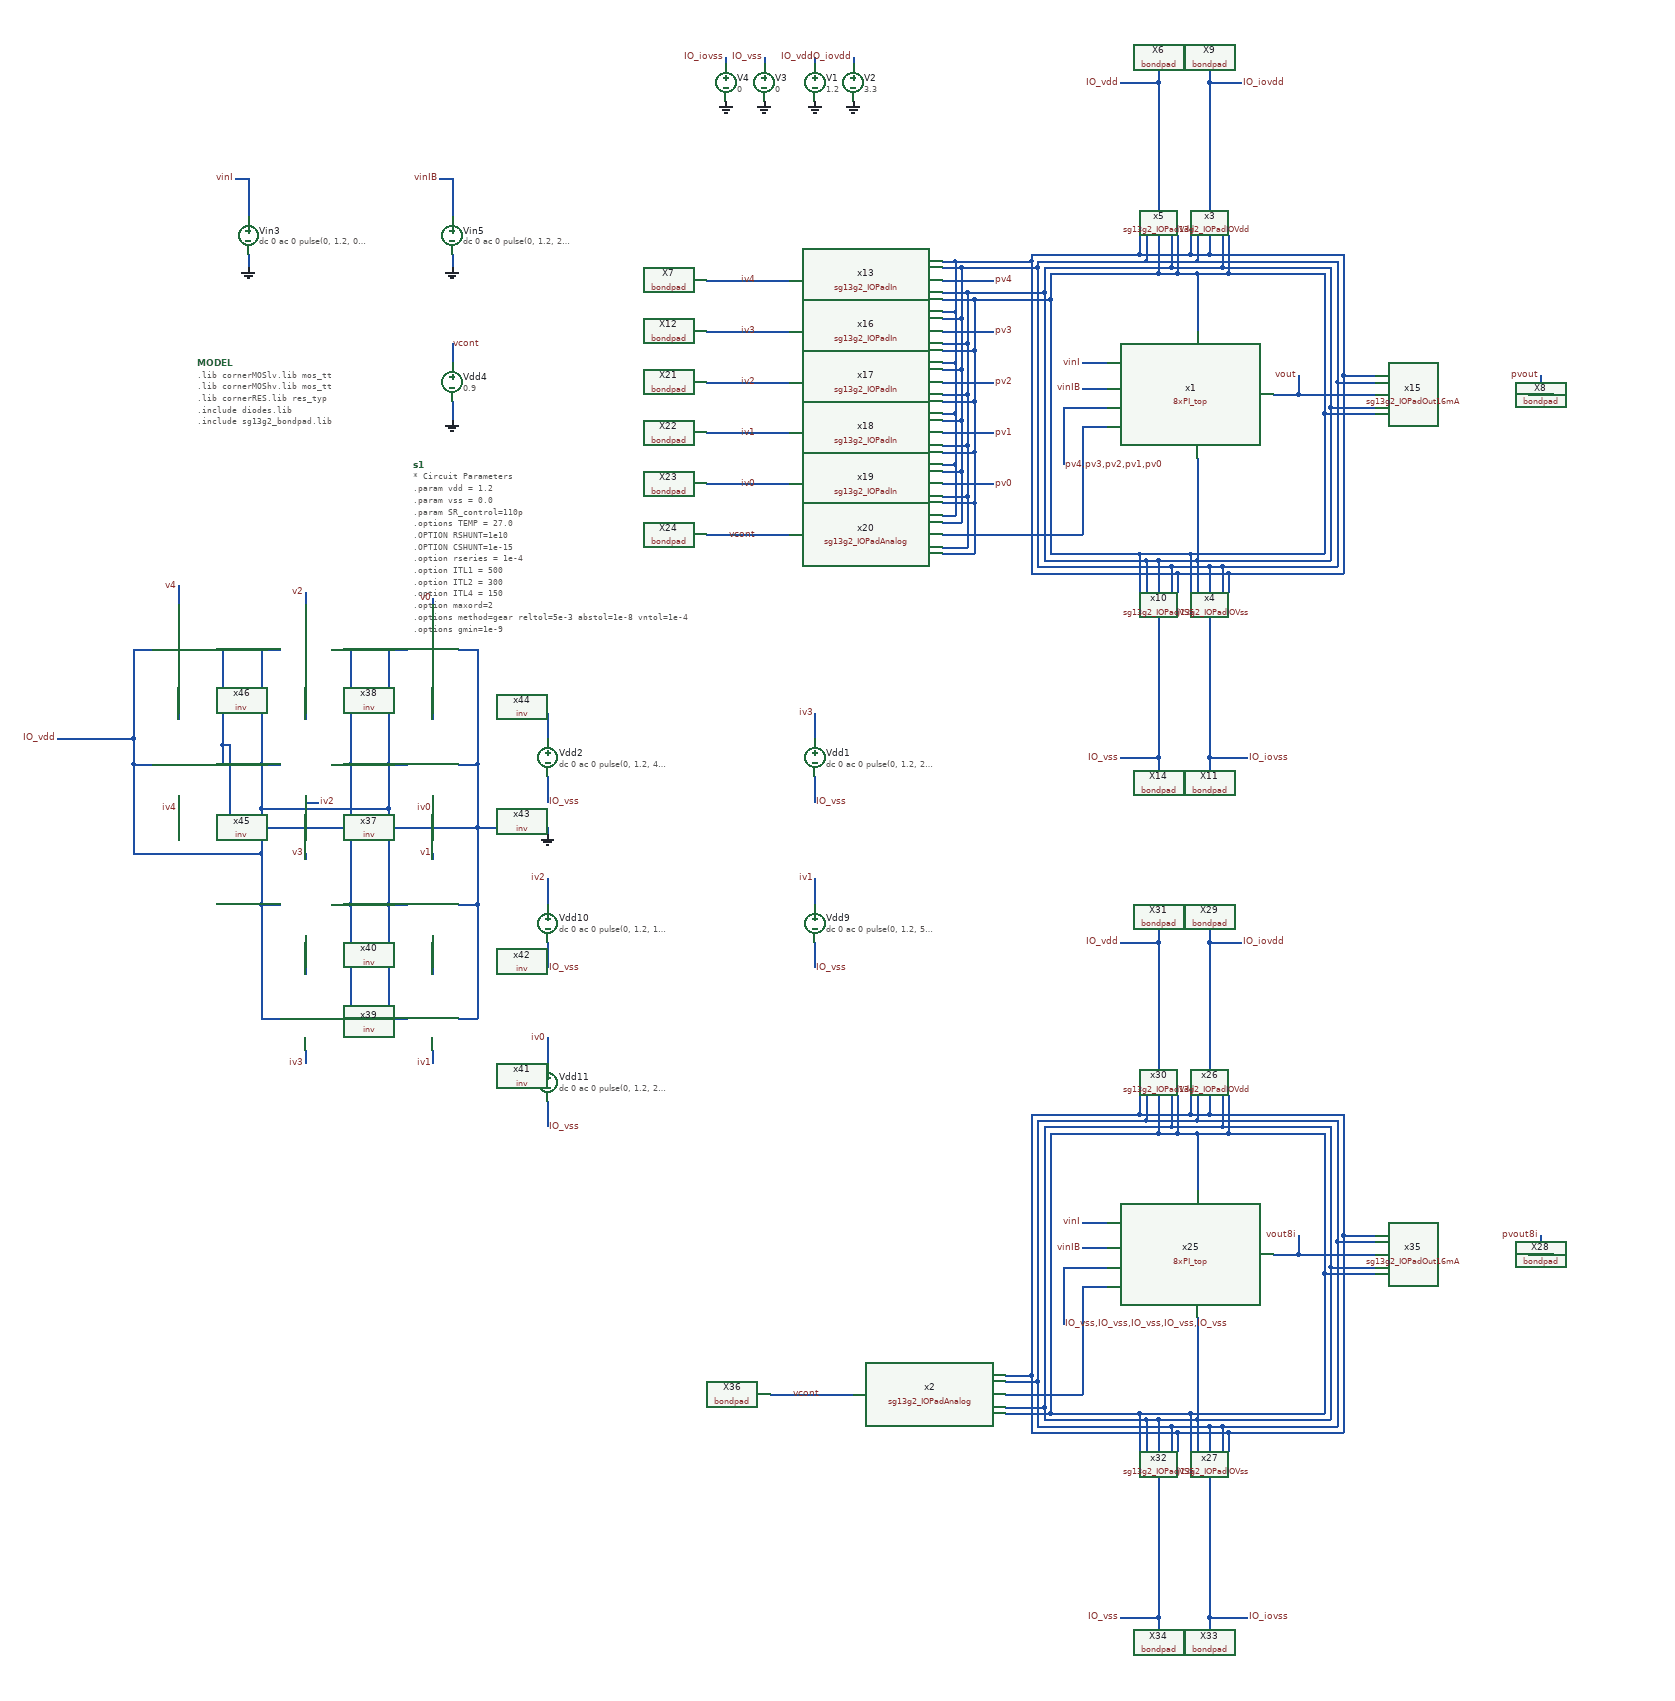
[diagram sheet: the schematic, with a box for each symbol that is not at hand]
v {xschem version=3.4.8RC file_version=1.3}
G {}
K {}
V {}
S {}
F {}
E {}
N -1470 -690 -1470 -670 {
lab=GND}
N -1470 -810 -1470 -750 {
lab=vinI}
N -1490 -810 -1470 -810 {
lab=vinI}
N -1150 -690 -1150 -670 {
lab=GND}
N -1150 -810 -1150 -750 {
lab=vinIB}
N -1170 -810 -1150 -810 {
lab=vinIB}
N -1000 290 -1000 330 {lab=iv2}
N -580 290 -580 330 {lab=iv1}
N -1000 390 -1000 430 {lab=IO_vss}
N -580 390 -580 430 {lab=IO_vss}
N -1000 540 -1000 580 {lab=iv0}
N -1000 640 -1000 680 {lab=IO_vss}
N -1000 30 -1000 70 {lab=iv4}
N -580 30 -580 70 {lab=iv3}
N -580 130 -580 170 {lab=IO_vss}
N -1150 -550 -1150 -520 {lab=vcont}
N -1150 -460 -1150 -430 {lab=GND}
N -160 -520 -120 -520 {lab=vinI}
N -160 -480 -120 -480 {lab=vinIB}
N -160 -420 -120 -420 {lab=#net1}
N 180 -470 300 -470 {lab=vout}
N 70 -660 220 -660 {lab=IO_vdd}
N 20 -680 240 -680 {lab=IO_iovss}
N 60 -200 240 -200 {lab=IO_iovss}
N 70 -190 250 -190 {lab=IO_iovdd}
N -220 -630 -220 -210 {lab=IO_vss}
N -230 -670 -230 -200 {lab=IO_iovss}
N -240 -680 -240 -190 {lab=IO_iovdd}
N 60 -670 230 -670 {lab=IO_vss}
N -210 -620 -210 -220 {lab=IO_vdd}
N -220 -210 -60 -210 {lab=IO_vss}
N 230 -450 230 -210 {lab=IO_vss}
N 240 -490 240 -200 {lab=IO_iovss}
N 220 -440 220 -220 {lab=IO_vdd}
N -520 -1000 -520 -990 {
lab=IO_iovdd}
N -720 -1000 -720 -990 {
lab=IO_iovss}
N 10 -720 10 -690 {lab=IO_iovdd}
N -70 -690 10 -690 {lab=IO_iovdd}
N 20 -720 20 -680 {lab=IO_iovss}
N -60 -680 20 -680 {lab=IO_iovss}
N 60 -720 60 -670 {lab=IO_vss}
N -20 -670 60 -670 {lab=IO_vss}
N 70 -720 70 -660 {lab=IO_vdd}
N 20 -660 20 -570 {lab=IO_vdd}
N -10 -660 20 -660 {lab=IO_vdd}
N 40 -690 250 -690 {lab=IO_iovdd}
N 70 -190 70 -160 {lab=IO_iovdd}
N -10 -190 70 -190 {lab=IO_iovdd}
N 60 -200 60 -160 {lab=IO_iovss}
N 40 -200 60 -200 {lab=IO_iovss}
N 20 -210 230 -210 {lab=IO_vss}
N 10 -220 10 -160 {lab=IO_vdd}
N -70 -220 10 -220 {lab=IO_vdd}
N 40 -960 90 -960 {lab=IO_iovdd}
N 40 -980 40 -960 {lab=IO_iovdd}
N 20 -660 70 -660 {lab=IO_vdd}
N 40 -960 40 -690 {lab=IO_iovdd}
N 10 -690 40 -690 {lab=IO_iovdd}
N -70 -720 -70 -690 {lab=IO_iovdd}
N -240 -690 -70 -690 {lab=IO_iovdd}
N -60 -720 -60 -680 {lab=IO_iovss}
N -230 -680 -60 -680 {lab=IO_iovss}
N -20 -720 -20 -670 {lab=IO_vss}
N -220 -670 -20 -670 {lab=IO_vss}
N -10 -720 -10 -660 {lab=IO_vdd}
N -40 -660 -10 -660 {lab=IO_vdd}
N -40 -960 -40 -660 {lab=IO_vdd}
N -210 -660 -40 -660 {lab=IO_vdd}
N -580 -1000 -580 -990 {
lab=IO_vdd}
N -660 -1000 -660 -990 {
lab=IO_vss}
N -10 -190 -10 -160 {lab=IO_iovdd}
N -240 -190 -10 -190 {lab=IO_iovdd}
N -20 -200 -20 -160 {lab=IO_iovss}
N -60 -210 -60 -160 {lab=IO_vss}
N -70 -220 -70 -160 {lab=IO_vdd}
N -210 -220 -70 -220 {lab=IO_vdd}
N -100 -960 -40 -960 {lab=IO_vdd}
N -40 -980 -40 -960 {lab=IO_vdd}
N 40 100 40 120 {lab=IO_iovss}
N -20 -200 40 -200 {lab=IO_iovss}
N -40 100 -40 120 {lab=IO_vss}
N -40 -210 20 -210 {lab=IO_vss}
N 40 100 100 100 {lab=IO_iovss}
N 40 -200 40 100 {lab=IO_iovss}
N -100 100 -40 100 {lab=IO_vss}
N 10 -220 220 -220 {lab=IO_vdd}
N 250 -500 250 -190 {lab=IO_iovdd}
N 250 -500 300 -500 {lab=IO_iovdd}
N 250 -690 250 -500 {lab=IO_iovdd}
N 240 -490 300 -490 {lab=IO_iovss}
N 240 -680 240 -490 {lab=IO_iovss}
N 230 -450 300 -450 {lab=IO_vss}
N 230 -670 230 -450 {lab=IO_vss}
N 220 -440 300 -440 {lab=IO_vdd}
N 220 -660 220 -440 {lab=IO_vdd}
N 560 -470 580 -470 {lab=pvout}
N -360 -680 -240 -680 {lab=IO_iovdd}
N -240 -690 -240 -680 {lab=IO_iovdd}
N -360 -360 -360 -280 {lab=IO_iovdd}
N -380 -680 -360 -680 {lab=IO_iovdd}
N -380 -280 -360 -280 {lab=IO_iovdd}
N -380 -360 -360 -360 {lab=IO_iovdd}
N -360 -440 -360 -360 {lab=IO_iovdd}
N -380 -440 -360 -440 {lab=IO_iovdd}
N -360 -520 -360 -440 {lab=IO_iovdd}
N -380 -520 -360 -520 {lab=IO_iovdd}
N -360 -600 -360 -520 {lab=IO_iovdd}
N -380 -600 -360 -600 {lab=IO_iovdd}
N -360 -680 -360 -600 {lab=IO_iovdd}
N -350 -670 -230 -670 {lab=IO_iovss}
N -230 -680 -230 -670 {lab=IO_iovss}
N -350 -350 -350 -270 {lab=IO_iovss}
N -380 -670 -350 -670 {lab=IO_iovss}
N -380 -270 -350 -270 {lab=IO_iovss}
N -380 -590 -350 -590 {lab=IO_iovss}
N -350 -670 -350 -590 {lab=IO_iovss}
N -380 -510 -350 -510 {lab=IO_iovss}
N -350 -590 -350 -510 {lab=IO_iovss}
N -380 -430 -350 -430 {lab=IO_iovss}
N -350 -510 -350 -430 {lab=IO_iovss}
N -380 -350 -350 -350 {lab=IO_iovss}
N -350 -430 -350 -350 {lab=IO_iovss}
N -340 -630 -220 -630 {lab=IO_vss}
N -220 -670 -220 -630 {lab=IO_vss}
N -340 -310 -340 -230 {lab=IO_vss}
N -380 -630 -340 -630 {lab=IO_vss}
N -380 -230 -340 -230 {lab=IO_vss}
N -380 -550 -340 -550 {lab=IO_vss}
N -340 -630 -340 -550 {lab=IO_vss}
N -380 -470 -340 -470 {lab=IO_vss}
N -340 -550 -340 -470 {lab=IO_vss}
N -380 -390 -340 -390 {lab=IO_vss}
N -340 -470 -340 -390 {lab=IO_vss}
N -380 -310 -340 -310 {lab=IO_vss}
N -340 -390 -340 -310 {lab=IO_vss}
N -330 -620 -210 -620 {lab=IO_vdd}
N -210 -660 -210 -620 {lab=IO_vdd}
N -330 -300 -330 -220 {lab=IO_vdd}
N -380 -620 -330 -620 {lab=IO_vdd}
N -380 -220 -330 -220 {lab=IO_vdd}
N -380 -540 -330 -540 {lab=IO_vdd}
N -330 -620 -330 -540 {lab=IO_vdd}
N -380 -460 -330 -460 {lab=IO_vdd}
N -330 -540 -330 -460 {lab=IO_vdd}
N -380 -380 -330 -380 {lab=IO_vdd}
N -330 -460 -330 -380 {lab=IO_vdd}
N -380 -300 -330 -300 {lab=IO_vdd}
N -330 -380 -330 -300 {lab=IO_vdd}
N -380 -250 -160 -250 {lab=#net1}
N -160 -420 -160 -250 {lab=#net1}
N -190 -450 -190 -360 {lab=pv4,pv3,pv2,pv1,pv0}
N -190 -450 -120 -450 {lab=pv4,pv3,pv2,pv1,pv0}
N -380 -650 -300 -650 {lab=pv4}
N -380 -570 -300 -570 {lab=pv3}
N -380 -490 -300 -490 {lab=pv2}
N -380 -410 -300 -410 {lab=pv1}
N -380 -330 -300 -330 {lab=pv0}
N 560 -500 560 -470 {lab=pvout}
N 540 -470 560 -470 {lab=pvout}
N 180 -500 180 -470 {lab=vout}
N 140 -470 180 -470 {lab=vout}
N -750 -650 -620 -650 {lab=iv4}
N -750 -570 -620 -570 {lab=iv3}
N -750 -490 -620 -490 {lab=iv2}
N -750 -410 -620 -410 {lab=iv1}
N -750 -330 -620 -330 {lab=iv0}
N -750 -250 -620 -250 {lab=vcont}
N -160 830 -120 830 {lab=vinI}
N -160 870 -120 870 {lab=vinIB}
N -160 930 -120 930 {lab=#net2}
N 180 880 300 880 {lab=vout8i}
N 70 690 220 690 {lab=IO_vdd}
N 20 670 240 670 {lab=IO_iovss}
N 60 1150 240 1150 {lab=IO_iovss}
N 70 1160 250 1160 {lab=IO_iovdd}
N 60 680 230 680 {lab=IO_vss}
N -220 1140 -60 1140 {lab=IO_vss}
N 230 900 230 1140 {lab=IO_vss}
N 240 860 240 1150 {lab=IO_iovss}
N 220 910 220 1130 {lab=IO_vdd}
N 10 630 10 660 {lab=IO_iovdd}
N -70 660 10 660 {lab=IO_iovdd}
N 20 630 20 670 {lab=IO_iovss}
N -60 670 20 670 {lab=IO_iovss}
N 60 630 60 680 {lab=IO_vss}
N -20 680 60 680 {lab=IO_vss}
N 70 630 70 690 {lab=IO_vdd}
N 20 690 20 780 {lab=IO_vdd}
N -10 690 20 690 {lab=IO_vdd}
N 40 660 250 660 {lab=IO_iovdd}
N 70 1160 70 1190 {lab=IO_iovdd}
N -10 1160 70 1160 {lab=IO_iovdd}
N 60 1150 60 1190 {lab=IO_iovss}
N 40 1150 60 1150 {lab=IO_iovss}
N 20 1140 230 1140 {lab=IO_vss}
N 10 1130 10 1190 {lab=IO_vdd}
N -70 1130 10 1130 {lab=IO_vdd}
N 40 390 90 390 {lab=IO_iovdd}
N 40 370 40 390 {lab=IO_iovdd}
N 20 690 70 690 {lab=IO_vdd}
N 40 390 40 660 {lab=IO_iovdd}
N 10 660 40 660 {lab=IO_iovdd}
N -70 630 -70 660 {lab=IO_iovdd}
N -240 660 -70 660 {lab=IO_iovdd}
N -60 630 -60 670 {lab=IO_iovss}
N -230 670 -60 670 {lab=IO_iovss}
N -20 630 -20 680 {lab=IO_vss}
N -220 680 -20 680 {lab=IO_vss}
N -10 630 -10 690 {lab=IO_vdd}
N -40 690 -10 690 {lab=IO_vdd}
N -40 390 -40 690 {lab=IO_vdd}
N -210 690 -40 690 {lab=IO_vdd}
N 20 1140 20 1190 {lab=IO_vss}
N -40 1140 20 1140 {lab=IO_vss}
N -10 1160 -10 1190 {lab=IO_iovdd}
N -240 1160 -10 1160 {lab=IO_iovdd}
N -20 1150 -20 1190 {lab=IO_iovss}
N -230 1150 -20 1150 {lab=IO_iovss}
N -60 1140 -60 1190 {lab=IO_vss}
N -70 1130 -70 1190 {lab=IO_vdd}
N -210 1130 -70 1130 {lab=IO_vdd}
N -100 390 -40 390 {lab=IO_vdd}
N -40 370 -40 390 {lab=IO_vdd}
N 40 1450 40 1470 {lab=IO_iovss}
N -20 1150 40 1150 {lab=IO_iovss}
N -40 1450 -40 1470 {lab=IO_vss}
N -60 1140 -40 1140 {lab=IO_vss}
N 40 1450 100 1450 {lab=IO_iovss}
N 40 1150 40 1450 {lab=IO_iovss}
N -100 1450 -40 1450 {lab=IO_vss}
N -40 1140 -40 1450 {lab=IO_vss}
N 10 1130 220 1130 {lab=IO_vdd}
N 250 850 250 1160 {lab=IO_iovdd}
N 250 850 300 850 {lab=IO_iovdd}
N 250 660 250 850 {lab=IO_iovdd}
N 240 860 300 860 {lab=IO_iovss}
N 240 670 240 860 {lab=IO_iovss}
N 230 900 300 900 {lab=IO_vss}
N 230 680 230 900 {lab=IO_vss}
N 220 910 300 910 {lab=IO_vdd}
N 220 690 220 910 {lab=IO_vdd}
N 560 880 580 880 {lab=pvout8i}
N -240 1070 -240 1160 {lab=IO_iovdd}
N -230 1080 -230 1150 {lab=IO_iovss}
N -220 1120 -220 1140 {lab=IO_vss}
N -210 690 -210 1130 {lab=IO_vdd}
N -160 930 -160 1100 {lab=#net2}
N -190 900 -190 990 {lab=IO_vss,IO_vss,IO_vss,IO_vss,IO_vss}
N -190 900 -120 900 {lab=IO_vss,IO_vss,IO_vss,IO_vss,IO_vss}
N 560 850 560 880 {lab=pvout8i}
N 540 880 560 880 {lab=pvout8i}
N 180 850 180 880 {lab=vout8i}
N 140 880 180 880 {lab=vout8i}
N -280 1070 -240 1070 {lab=IO_iovdd}
N -240 660 -240 1070 {lab=IO_iovdd}
N -280 1080 -230 1080 {lab=IO_iovss}
N -230 670 -230 1080 {lab=IO_iovss}
N -280 1100 -160 1100 {lab=#net2}
N -280 1120 -220 1120 {lab=IO_vss}
N -220 680 -220 1120 {lab=IO_vss}
N -280 1130 -210 1130 {lab=IO_vdd}
N -650 1100 -520 1100 {lab=vcont}
N 20 -370 20 -210 {lab=IO_vss}
N 20 980 20 1140 {lab=IO_vss}
N -230 -200 -20 -200 {lab=IO_iovss}
N -40 -210 -40 100 {lab=IO_vss}
N -60 -210 -40 -210 {lab=IO_vss}
N 20 -210 20 -160 {lab=IO_vss}
N -1540 -70 -1510 -70 {lab=GND}
N -1510 80 -1510 110 {lab=GND}
N -1540 110 -1510 110 {lab=GND}
N -1340 -70 -1310 -70 {lab=GND}
N -1310 330 -1310 510 {lab=GND}
N -1340 510 -1310 510 {lab=GND}
N -1340 330 -1310 330 {lab=GND}
N -1310 210 -1310 330 {lab=GND}
N -1340 110 -1310 110 {lab=GND}
N -1310 -70 -1310 110 {lab=GND}
N -1140 -70 -1110 -70 {lab=GND}
N -1110 330 -1110 510 {lab=GND}
N -1140 510 -1110 510 {lab=GND}
N -1140 330 -1110 330 {lab=GND}
N -1110 210 -1110 330 {lab=GND}
N -1140 110 -1110 110 {lab=GND}
N -1110 -70 -1110 110 {lab=GND}
N -1650 -70 -1620 -70 {lab=IO_vdd}
N -1650 110 -1620 110 {lab=IO_vdd}
N -1450 -70 -1420 -70 {lab=IO_vdd}
N -1450 330 -1450 510 {lab=IO_vdd}
N -1450 510 -1420 510 {lab=IO_vdd}
N -1450 330 -1420 330 {lab=IO_vdd}
N -1450 250 -1450 330 {lab=IO_vdd}
N -1450 110 -1420 110 {lab=IO_vdd}
N -1450 -70 -1450 110 {lab=IO_vdd}
N -1250 -70 -1220 -70 {lab=IO_vdd}
N -1250 330 -1250 510 {lab=IO_vdd}
N -1250 510 -1220 510 {lab=IO_vdd}
N -1250 330 -1220 330 {lab=IO_vdd}
N -1250 180 -1250 330 {lab=IO_vdd}
N -1250 110 -1220 110 {lab=IO_vdd}
N -1250 -70 -1250 110 {lab=IO_vdd}
N -1510 80 -1500 80 {lab=GND}
N -1510 -70 -1510 80 {lab=GND}
N -1500 80 -1500 210 {lab=GND}
N -1500 210 -1310 210 {lab=GND}
N -1310 110 -1310 210 {lab=GND}
N -1310 210 -1110 210 {lab=GND}
N -1110 110 -1110 210 {lab=GND}
N -1110 210 -1000 210 {lab=GND}
N -1770 70 -1650 70 {lab=IO_vdd}
N -1650 -70 -1650 70 {lab=IO_vdd}
N -1650 110 -1650 250 {lab=IO_vdd}
N -1650 70 -1650 110 {lab=IO_vdd}
N -1650 250 -1450 250 {lab=IO_vdd}
N -1450 180 -1450 250 {lab=IO_vdd}
N -1450 180 -1250 180 {lab=IO_vdd}
N -1450 110 -1450 180 {lab=IO_vdd}
N -1250 110 -1250 180 {lab=IO_vdd}
N -1180 -20 -1180 40 {lab=#net3}
N -1380 -20 -1380 40 {lab=#net4}
N -1580 -20 -1580 40 {lab=#net5}
N -1380 380 -1380 440 {lab=#net6}
N -1180 380 -1180 440 {lab=#net7}
N -1580 160 -1580 180 {lab=iv4}
N -1380 560 -1380 580 {lab=iv3}
N -1380 170 -1360 170 {lab=iv2}
N -1380 160 -1380 170 {lab=iv2}
N -1180 560 -1180 580 {lab=iv1}
N -1180 160 -1180 180 {lab=iv0}
N -1580 -170 -1580 -140 {lab=v4}
N -1380 250 -1380 260 {lab=v3}
N -1380 -160 -1380 -140 {lab=v2}
N -1180 250 -1180 260 {lab=v1}
N -1180 -150 -1180 -140 {lab=v0}
N -1000 130 -1000 170 {lab=IO_vss}
N -1000 210 -1000 220 {lab=GND}
C {8xPI_top/8xPI_top.sym} 20 -470 0 0 {name=x1}
C {devices/gnd.sym} -1470 -670 0 0 {name=l2 lab=GND}
C {devices/vsource.sym} -1470 -720 0 0 {name=Vin3 value="dc 0 ac 0 pulse(0, 1.2, 0, 50p, 50p, 200p, 500p) "}
C {devices/lab_pin.sym} -1490 -810 0 0 {name=p1 sig_type=std_logic lab=vinI}
C {devices/gnd.sym} -1150 -670 0 0 {name=l4 lab=GND}
C {devices/vsource.sym} -1150 -720 0 0 {name=Vin5 value="dc 0 ac 0 pulse(0, 1.2, 250p, 50p, 50p, 200p, 500p ) "}
C {devices/lab_pin.sym} -1170 -810 0 0 {name=p3 sig_type=std_logic lab=vinIB}
C {devices/lab_pin.sym} -160 -520 0 0 {name=p4 sig_type=std_logic lab=vinI}
C {devices/lab_pin.sym} -160 -480 0 0 {name=p7 sig_type=std_logic lab=vinIB}
C {devices/vsource.sym} -580 360 0 0 {name=Vdd9 value="dc 0 ac 0 pulse(0, 1.2, 5n,\{SR_control\},\{SR_control\}, 5n, 10n)"}
C {devices/vsource.sym} -1000 360 0 0 {name=Vdd10 value="dc 0 ac 0 pulse(0, 1.2, 10n,\{SR_control\},\{SR_control\}, 10n, 20n) "}
C {devices/lab_pin.sym} -1000 290 0 0 {name=p49 sig_type=std_logic lab=iv2}
C {devices/lab_pin.sym} -580 290 0 0 {name=p50 sig_type=std_logic lab=iv1}
C {devices/lab_pin.sym} -1000 430 2 0 {name=p51 sig_type=std_logic lab=IO_vss}
C {devices/lab_pin.sym} -580 430 2 0 {name=p52 sig_type=std_logic lab=IO_vss}
C {devices/vsource.sym} -1000 610 0 0 {name=Vdd11 value="dc 0 ac 0 pulse(0, 1.2, 2.5n,\{SR_control\},\{SR_control\}, 2.5n, 5n)"}
C {devices/lab_pin.sym} -1000 540 0 0 {name=p53 sig_type=std_logic lab=iv0}
C {devices/lab_pin.sym} -1000 680 2 0 {name=p54 sig_type=std_logic lab=IO_vss}
C {devices/vsource.sym} -580 100 0 0 {name=Vdd1 value="dc 0 ac 0 pulse(0, 1.2, 20n,\{SR_control\},\{SR_control\}, 20n, 40n)"}
C {devices/vsource.sym} -1000 100 0 0 {name=Vdd2 value="dc 0 ac 0 pulse(0, 1.2, 40n,\{SR_control\},\{SR_control\}, 40n, 80n) "}
C {devices/lab_pin.sym} -1000 30 0 0 {name=p11 sig_type=std_logic lab=iv4}
C {devices/lab_pin.sym} -580 30 0 0 {name=p10 sig_type=std_logic lab=iv3}
C {devices/lab_pin.sym} -1000 170 2 0 {name=p2 sig_type=std_logic lab=IO_vss}
C {devices/lab_pin.sym} -580 170 2 0 {name=p9 sig_type=std_logic lab=IO_vss}
C {devices/lab_pin.sym} -190 -360 2 0 {name=p30 sig_type=std_logic lab="pv4,pv3,pv2,pv1,pv0"}
C {devices/lab_pin.sym} -1150 -550 2 0 {name=p12 sig_type=std_logic lab=vcont}
C {devices/vsource.sym} -1150 -490 0 0 {name=Vdd4 value=0.9 savecurrent=false
}
C {devices/gnd.sym} -1150 -430 0 0 {name=l9 lab=GND}
C {devices/lab_pin.sym} 560 -500 1 0 {name=p22 sig_type=std_logic lab=pvout}
C {netlist_not_shown.sym} -1210 -360 0 0 {name=s1 only_toplevel=true 

value="

* Circuit Parameters
.param vdd = 1.2
.param vss = 0.0
.param SR_control=110p
.options TEMP = 27.0
.OPTION RSHUNT=1e10
.OPTION CSHUNT=1e-15
.option rseries = 1e-4
.option ITL1 = 500
.option ITL2 = 300
.option ITL4 = 150
.option maxord=2
.options method=gear reltol=5e-3 abstol=1e-8 vntol=1e-4
.options gmin=1e-9
.options pivtol=1e-10
.options chgtol=1e-12

* Include Models
*.lib /opt/pdks/ihp-sg13g2/libs.tech/ngspice/models/cornerMOSlv.lib mos_tt
*.lib /opt/pdks/ihp-sg13g2/libs.tech/ngspice/models/cornerMOShv.lib mos_tt
*.lib /opt/pdks/ihp-sg13g2/libs.tech/ngspice/models/cornerHBT.lib hbt_typ
*.lib /opt/pdks/ihp-sg13g2/libs.tech/ngspice/models/cornerRES.lib res_typ
*.lib cornerMOSlv.lib mos_tt


* OP Parameters & Singals to save
.save V(vout) V(pvout) V(vout8i) V(pvout8i) V(vinI) V(vinIB) V(x1.vsq[2]) V(x1.vsq[1]) V(x1.vsq[0]) V(x1.vst[7]) V(x1.vst[6]) V(x1.vst[5]) V(x1.vst[4]) V(x1.vst[3]) V(x1.vst[2]) V(x1.vst[1]) V(x1.vstq[7]) V(x1.vstq[6]) V(x1.vstq[5]) V(x1.vstq[4]) V(x1.vstq[3]) V(x1.vstq[2]) V(x1.vstq[1]) V(x1.vi) V(x1.vib) V(x1.vq) V(x1.vqb)

*Simulations
.control
*set output_path = tb_linearity_8xpi/
	tran 100PS 80NS
	*setplot tran1
	*plot v0 v1+1.5 v0_st+3 v6_st+4.5 Vout+6 Vout8I+7.5 ylabel vout xlabel vin
	display
	set filetype = ascii
        write tran_linearity_integration.raw 
	*V(vout) V(vout8i) V(vinI) V(vinIB) V(@x1.vsq[2]) V(x1.vst[7]) V(x1.vstq[7]) V(x1.x1.vini) V(x1.x1.vinib) V(x1.x1.vinq) V(x1.x1.vinqb)
	*write \{$output_path\}tran_linearity_termoless.raw V(Vout) V(Vout8I) V(vinI) V(VoutI1) V(VoutI2) V(VoutQ1) V(VoutIB1) V(VoutQB1)
.endc
.end"}
C {lab_pin.sym} 90 -960 2 0 {name=p23 sig_type=std_logic lab=IO_iovdd}
C {project_io/sg13g2_IOPadIOVdd/sg13g2_IOPadIOVdd.sym} 40 -840 3 0 {name=x3}
C {project_io/sg13g2_IOPadIOVss/sg13g2_IOPadIOVss.sym} 40 -40 1 0 {name=x4}
C {sg13g2_pr/bondpad.sym} 620 -470 1 0 {name=X8
model=bondpad
spiceprefix=X
size=80u
shape=0
padtype=0
}
C {sg13g2_pr/bondpad.sym} 40 -1020 0 0 {name=X9
model=bondpad
spiceprefix=X
size=80u
shape=0
padtype=0
}
C {vsource.sym} -520 -960 0 0 {name=V2 value=3.3
}
C {gnd.sym} -520 -930 0 0 {name=l5 lab=GND}
C {lab_pin.sym} -520 -1000 1 0 {name=p31 sig_type=std_logic lab=IO_iovdd}
C {vsource.sym} -720 -960 0 0 {name=V4 value=0 savecurrent=false}
C {gnd.sym} -720 -930 0 0 {name=l8 lab=GND}
C {lab_pin.sym} -720 -1000 1 0 {name=p35 sig_type=std_logic lab=IO_iovss}
C {project_io/sg13g2_IOPadVdd/sg13g2_IOPadVdd.sym} -40 -840 3 0 {name=x5}
C {sg13g2_pr/bondpad.sym} -40 -1020 0 0 {name=X6
model=bondpad
spiceprefix=X
size=80u
shape=0
padtype=0
}
C {vsource.sym} -580 -960 0 0 {name=V1 value=1.2}
C {gnd.sym} -580 -930 0 0 {name=l3 lab=GND}
C {lab_pin.sym} -580 -1000 1 0 {name=p17 sig_type=std_logic lab=IO_vdd}
C {vsource.sym} -660 -960 0 0 {name=V3 value=0 savecurrent=false}
C {gnd.sym} -660 -930 0 0 {name=l7 lab=GND}
C {lab_pin.sym} -660 -1000 1 0 {name=p25 sig_type=std_logic lab=IO_vss}
C {project_io/sg13g2_IOPadVSS/sg13g2_IOPadVSS.sym} -40 -40 1 0 {name=x10}
C {lab_pin.sym} -100 -960 0 0 {name=p26 sig_type=std_logic lab=IO_vdd}
C {sg13g2_pr/bondpad.sym} 40 160 2 0 {name=X11
model=bondpad
spiceprefix=X
size=80u
shape=0
padtype=0
}
C {sg13g2_pr/bondpad.sym} -40 160 2 0 {name=X14
model=bondpad
spiceprefix=X
size=80u
shape=0
padtype=0
}
C {lab_pin.sym} 100 100 2 0 {name=p29 sig_type=std_logic lab=IO_iovss}
C {lab_pin.sym} -100 100 0 0 {name=p34 sig_type=std_logic lab=IO_vss}
C {project_io/sg13g2_IOPadOut16mA/sg13g2_IOPadOut16mA.sym} 420 -470 0 0 {name=x15}
C {project_io/sg13g2_IOPadIn/sg13g2_IOPadIn.sym} -500 -650 0 1 {name=x13}
C {project_io/sg13g2_IOPadIn/sg13g2_IOPadIn.sym} -500 -570 0 1 {name=x16}
C {project_io/sg13g2_IOPadIn/sg13g2_IOPadIn.sym} -500 -490 0 1 {name=x17}
C {project_io/sg13g2_IOPadIn/sg13g2_IOPadIn.sym} -500 -410 0 1 {name=x18}
C {project_io/sg13g2_IOPadIn/sg13g2_IOPadIn.sym} -500 -330 0 1 {name=x19}
C {project_io/sg13g2_IOPadAnalog/sg13g2_IOPadAnalog.sym} -500 -250 0 1 {name=x20}
C {lab_pin.sym} -670 -650 1 0 {name=p19 sig_type=std_logic lab=iv4}
C {devices/lab_pin.sym} -670 -250 1 0 {name=p15 sig_type=std_logic lab=vcont}
C {lab_pin.sym} -670 -570 1 0 {name=p24 sig_type=std_logic lab=iv3
}
C {lab_pin.sym} -670 -490 1 0 {name=p32 sig_type=std_logic lab=iv2}
C {lab_pin.sym} -670 -410 1 0 {name=p33 sig_type=std_logic lab=iv1}
C {lab_pin.sym} -670 -330 1 0 {name=p36 sig_type=std_logic lab=iv0}
C {lab_pin.sym} -300 -650 2 0 {name=p37 sig_type=std_logic lab=pv4}
C {lab_pin.sym} -300 -570 2 0 {name=p38 sig_type=std_logic lab=pv3}
C {lab_pin.sym} -300 -490 2 0 {name=p39 sig_type=std_logic lab=pv2}
C {lab_pin.sym} -300 -410 2 0 {name=p40 sig_type=std_logic lab=pv1}
C {lab_pin.sym} -300 -330 2 0 {name=p41 sig_type=std_logic lab=pv0}
C {devices/lab_pin.sym} 180 -500 1 0 {name=p27 sig_type=std_logic lab=vout}
C {sg13g2_pr/bondpad.sym} -790 -650 3 0 {name=X7
model=bondpad
spiceprefix=X
size=80u
shape=0
padtype=0
}
C {sg13g2_pr/bondpad.sym} -790 -570 3 0 {name=X12
model=bondpad
spiceprefix=X
size=80u
shape=0
padtype=0
}
C {sg13g2_pr/bondpad.sym} -790 -490 3 0 {name=X21
model=bondpad
spiceprefix=X
size=80u
shape=0
padtype=0
}
C {sg13g2_pr/bondpad.sym} -790 -410 3 0 {name=X22
model=bondpad
spiceprefix=X
size=80u
shape=0
padtype=0
}
C {sg13g2_pr/bondpad.sym} -790 -330 3 0 {name=X23
model=bondpad
spiceprefix=X
size=80u
shape=0
padtype=0
}
C {sg13g2_pr/bondpad.sym} -790 -250 3 0 {name=X24
model=bondpad
spiceprefix=X
size=80u
shape=0
padtype=0
}
C {8xPI_top/8xPI_top.sym} 20 880 0 0 {name=x25}
C {devices/lab_pin.sym} -160 830 0 0 {name=p28 sig_type=std_logic lab=vinI}
C {devices/lab_pin.sym} -160 870 0 0 {name=p42 sig_type=std_logic lab=vinIB}
C {devices/lab_pin.sym} -190 990 2 0 {name=p43 sig_type=std_logic lab="IO_vss,IO_vss,IO_vss,IO_vss,IO_vss"}
C {devices/lab_pin.sym} 560 850 1 0 {name=p44 sig_type=std_logic lab=pvout8i}
C {lab_pin.sym} 90 390 2 0 {name=p45 sig_type=std_logic lab=IO_iovdd}
C {project_io/sg13g2_IOPadIOVdd/sg13g2_IOPadIOVdd.sym} 40 510 3 0 {name=x26}
C {project_io/sg13g2_IOPadIOVss/sg13g2_IOPadIOVss.sym} 40 1310 1 0 {name=x27}
C {sg13g2_pr/bondpad.sym} 620 880 1 0 {name=X28
model=bondpad
spiceprefix=X
size=80u
shape=0
padtype=0
}
C {sg13g2_pr/bondpad.sym} 40 330 0 0 {name=X29
model=bondpad
spiceprefix=X
size=80u
shape=0
padtype=0
}
C {project_io/sg13g2_IOPadVdd/sg13g2_IOPadVdd.sym} -40 510 3 0 {name=x30}
C {sg13g2_pr/bondpad.sym} -40 330 0 0 {name=X31
model=bondpad
spiceprefix=X
size=80u
shape=0
padtype=0
}
C {project_io/sg13g2_IOPadVSS/sg13g2_IOPadVSS.sym} -40 1310 1 0 {name=x32}
C {lab_pin.sym} -100 390 0 0 {name=p46 sig_type=std_logic lab=IO_vdd}
C {sg13g2_pr/bondpad.sym} 40 1510 2 0 {name=X33
model=bondpad
spiceprefix=X
size=80u
shape=0
padtype=0
}
C {sg13g2_pr/bondpad.sym} -40 1510 2 0 {name=X34
model=bondpad
spiceprefix=X
size=80u
shape=0
padtype=0
}
C {lab_pin.sym} 100 1450 2 0 {name=p47 sig_type=std_logic lab=IO_iovss}
C {lab_pin.sym} -100 1450 0 0 {name=p48 sig_type=std_logic lab=IO_vss}
C {project_io/sg13g2_IOPadOut16mA/sg13g2_IOPadOut16mA.sym} 420 880 0 0 {name=x35}
C {devices/lab_pin.sym} 180 850 1 0 {name=p55 sig_type=std_logic lab=vout8i}
C {project_io/sg13g2_IOPadAnalog/sg13g2_IOPadAnalog.sym} -400 1100 0 1 {name=x2}
C {devices/lab_pin.sym} -570 1100 1 0 {name=p5 sig_type=std_logic lab=vcont}
C {sg13g2_pr/bondpad.sym} -690 1100 3 0 {name=X36
model=bondpad
spiceprefix=X
size=80u
shape=0
padtype=0
}
C {devices/code_shown.sym} -1550 -520 0 0 {name=MODEL only_toplevel=true
format="tcleval( @value )"
value="
.lib cornerMOSlv.lib mos_tt
.lib cornerMOShv.lib mos_tt
.lib cornerRES.lib res_typ
.include diodes.lib
.include sg13g2_bondpad.lib
"}
C {inv/inv.sym} -1240 200 3 0 {name=x37}
C {inv/inv.sym} -1240 20 3 0 {name=x38}
C {inv/inv.sym} -1240 600 3 0 {name=x39}
C {inv/inv.sym} -1240 420 3 0 {name=x40}
C {inv/inv.sym} -1040 600 3 0 {name=x41}
C {inv/inv.sym} -1040 420 3 0 {name=x42}
C {inv/inv.sym} -1040 200 3 0 {name=x43}
C {inv/inv.sym} -1040 20 3 0 {name=x44}
C {inv/inv.sym} -1440 200 3 0 {name=x45}
C {inv/inv.sym} -1440 20 3 0 {name=x46}
C {devices/lab_pin.sym} -1770 70 0 0 {name=p6 sig_type=std_logic lab=IO_vdd}
C {devices/lab_pin.sym} -1380 580 3 0 {name=p13 sig_type=std_logic lab=iv3}
C {devices/lab_pin.sym} -1360 170 2 0 {name=p14 sig_type=std_logic lab=iv2}
C {devices/lab_pin.sym} -1180 580 3 0 {name=p16 sig_type=std_logic lab=iv1}
C {devices/lab_pin.sym} -1180 180 3 0 {name=p18 sig_type=std_logic lab=iv0}
C {devices/lab_pin.sym} -1580 180 3 0 {name=p20 sig_type=std_logic lab=iv4}
C {devices/lab_pin.sym} -1580 -170 1 0 {name=p21 sig_type=std_logic lab=v4}
C {devices/lab_pin.sym} -1380 250 1 0 {name=p56 sig_type=std_logic lab=v3}
C {devices/lab_pin.sym} -1380 -160 1 0 {name=p57 sig_type=std_logic lab=v2}
C {devices/lab_pin.sym} -1180 250 1 0 {name=p58 sig_type=std_logic lab=v1}
C {devices/lab_pin.sym} -1180 -150 1 0 {name=p59 sig_type=std_logic lab=v0}
C {devices/gnd.sym} -1000 220 0 0 {name=l1 lab=GND}
